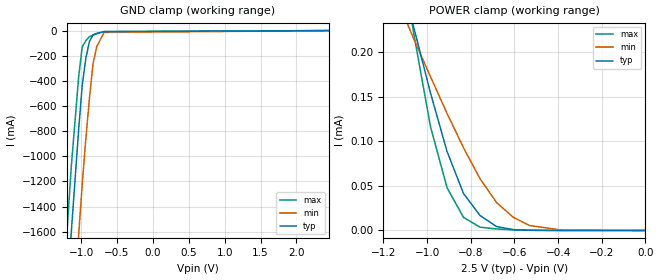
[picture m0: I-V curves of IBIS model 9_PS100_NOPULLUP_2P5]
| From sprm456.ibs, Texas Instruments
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|   Model Cell 9_PS100_NOPULLUP_2P5
|IDG09_PS100_NOPULLUP_2P5
[Model]   9_PS100_NOPULLUP_2P5
Model_type   Input
Polarity   Non-Inverting
Vinl =  0.7V
Vinh =  1.7V
C_comp   1.242p   1.179p   1.348p
[Model Spec]
Vinl   0.7V   0.7V   0.7V
Vinh   1.7V   1.7V   1.7V
[Temperature Range]   25   125   -40
[Voltage Range]   2.5   2.3   2.7
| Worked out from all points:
|   GND clamp passes 1 mA (typ) near -0.54 V on its own axis
|   POWER clamp passes 1 mA (typ) near -1.78 V on its own axis
[POWER_clamp]
|   voltage   I(typ)   I(min)   I(max)
-2.5V     1.799mA    1.079mA    2.669mA
-1.086V   252.9uA    229.2uA    259uA
-1.061V   227.3uA    214.7uA    220.2uA
-984.8mV  154.2uA    172.4uA    116.6uA
-909.1mV  88.74uA    131.4uA    48.03uA
-833.3mV  41.32uA    92.61uA    14.65uA
-757.6mV  16.76uA    57.96uA    3.67uA
-681.8mV  4.381uA    31.2uA     1.697uA
-606.1mV  983.2nA    14.9uA     689.9nA
-530.3mV  264.7nA    5.536uA    165nA
-378.8mV  6.024nA    207.4nA    1.209nA
0V        45.52pA    7.544nA    444.1fA
[GND_clamp]
|   voltage   I(typ)   I(min)   I(max)
-2.5V     -14.65A    -15.5A     -14.18A
-1.237V   -2.489A    -3.395A    -1.958A
-1.187V   -2.038A    -2.94A     -1.511A
-1.136V   -1.594A    -2.491A    -1.074A
-1.035V   -791.1mA   -1.633A    -371.4mA
-984.8mV  -434.4mA   -1.223A    -129.3mA
-934.3mV  -219.3mA   -857.5mA   -79.97mA
-883.8mV  -85.7mA    -536.6mA   -48.63mA
-833.3mV  -33.72mA   -260.3mA   -35.29mA
-782.8mV  -22.94mA   -128.2mA   -24.88mA
-681.8mV  -8.355mA   -14.96mA   -8.084mA
2.449V    44.7pA     8.423nA    441.1fA
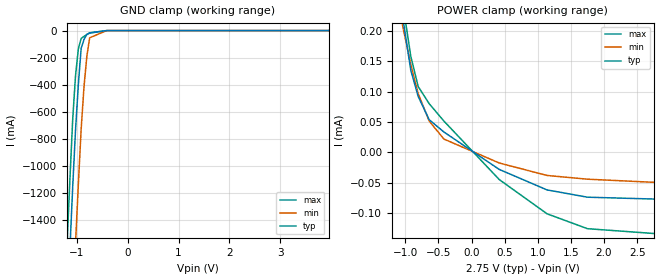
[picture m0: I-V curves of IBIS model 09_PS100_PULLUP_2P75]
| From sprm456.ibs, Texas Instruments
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|   Model Cell 09_PS100_PULLUP_2P75
|IDG09_PS100_PULLUP_2P75
[Model]   09_PS100_PULLUP_2P75
Model_type   Input
Polarity   Non-Inverting
Vinl =  0.7V
Vinh =  1.7V
C_comp   1.261p   1.175p   1.435p
[Model Spec]
Vinl   0.7V   0.7V   0.7V
Vinh   1.7V   1.7V   1.7V
[Temperature Range]   25   125   -40
[Voltage Range]   2.75   2.5   3
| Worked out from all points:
|   GND clamp passes 1 mA (typ) near -0.53 V on its own axis
|   POWER clamp passes 1 mA (typ) near -1.78 V on its own axis
[POWER_clamp]
|   voltage   I(typ)   I(min)   I(max)
-2.75V    2.08mA     1.234mA    3.107mA
-1.139V   317.1uA    263.9uA    365.7uA
-1.083V   262.8uA    232.7uA    289.5uA
-1.028V   213.9uA    202.4uA    237.9uA
-916.7mV  135.2uA    144.5uA    158.1uA
-805.6mV  92.07uA    96.77uA    108.4uA
-638.9mV  53.54uA    51.31uA    79.97uA
-416.7mV  33.34uA    21.7uA     51.35uA
416.7mV   -28.3uA    -17.73uA   -44.92uA
1.139V    -62.16uA   -38.31uA   -101.5uA
1.75V     -74.15uA   -44.46uA   -126.1uA
2.75V     -77.21uA   -49.64uA   -134uA
[GND_clamp]
|   voltage   I(typ)   I(min)   I(max)
-2.75V    -17.11A    -17.95A    -16.64A
-1.194V   -2.105A    -3.008A    -1.577A
-1.139V   -1.621A    -2.516A    -1.105A
-1.083V   -1.151A    -2.031A    -653.7mA
-1.028V   -736.7mA   -1.572A    -333.4mA
-972.2mV  -396.6mA   -1.136A    -134.9mA
-916.7mV  -130.4mA   -725.1mA   -58.16mA
-861.1mV  -66.01mA   -415.2mA   -43mA
-805.6mV  -28.03mA   -191.3mA   -29.76mA
-750mV    -16.53mA   -53.31mA   -18.44mA
-416.7mV  -107.7uA   -218.9uA   -140.6uA
5.5V      0A         0A         0A
